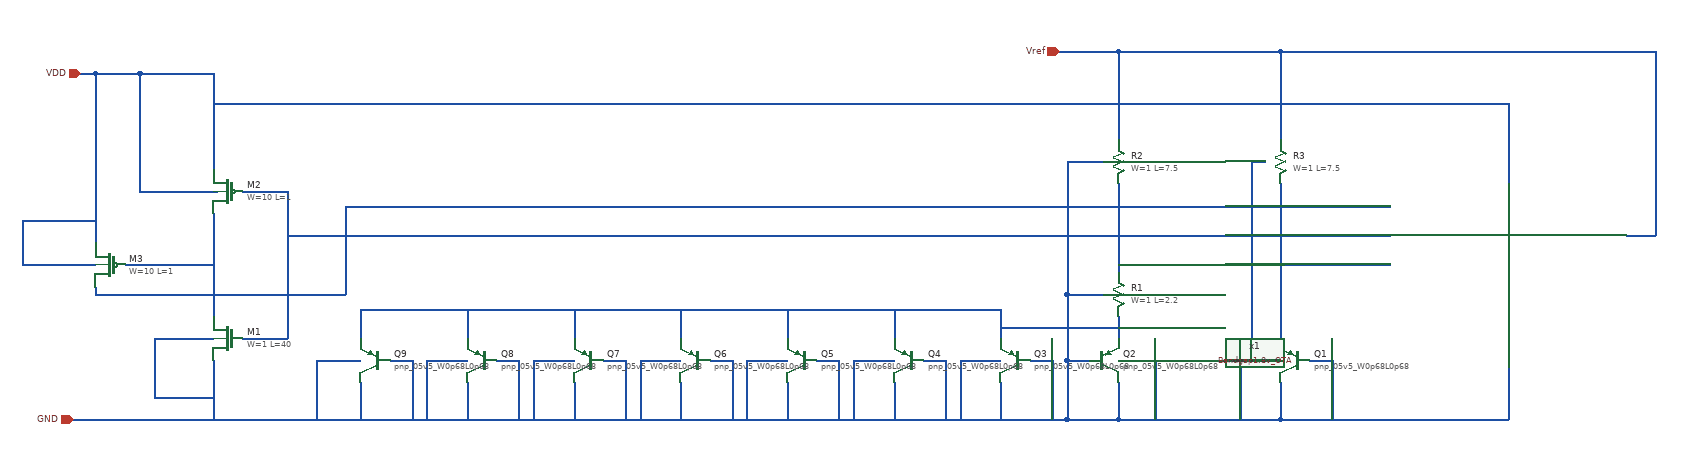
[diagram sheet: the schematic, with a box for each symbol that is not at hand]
v {xschem version=2.9.9 file_version=1.2 }
G {}
K {}
V {}
S {}
E {}
N -950 -260 -950 -210 { lab=GND}
N -1170 -260 -1170 -210 { lab=GND}
N -1170 -210 -950 -210 { lab=GND}
N -1170 -350 -1170 -320 { lab=#net1}
N -1170 -530 -1170 -410 { lab=#net2}
N -1170 -710 -950 -710 { lab=Vref}
N -1170 -710 -1170 -590 { lab=Vref}
N -950 -210 -660 -210 { lab=GND}
N -1250 -710 -1170 -710 { lab=Vref}
N -910 -290 -880 -290 { lab=GND}
N -880 -290 -880 -210 { lab=GND}
N -1005 -290 -950 -290 { lab=GND}
N -1005 -290 -1005 -210 { lab=GND}
N -1170 -290 -1120 -290 { lab=GND}
N -1120 -290 -1120 -210 { lab=GND}
N -1240 -290 -1210 -290 { lab=GND}
N -1240 -290 -1240 -210 { lab=GND}
N -1240 -210 -1170 -210 { lab=GND}
N -1330 -260 -1330 -210 { lab=GND}
N -1290 -290 -1260 -290 { lab=GND}
N -1260 -290 -1260 -210 { lab=GND}
N -1385 -290 -1330 -290 { lab=GND}
N -1385 -290 -1385 -210 { lab=GND}
N -1475 -260 -1475 -210 { lab=GND}
N -1435 -290 -1405 -290 { lab=GND}
N -1405 -290 -1405 -210 { lab=GND}
N -1530 -290 -1475 -290 { lab=GND}
N -1530 -290 -1530 -210 { lab=GND}
N -1620 -260 -1620 -210 { lab=GND}
N -1580 -290 -1550 -290 { lab=GND}
N -1550 -290 -1550 -210 { lab=GND}
N -1675 -290 -1620 -290 { lab=GND}
N -1675 -290 -1675 -210 { lab=GND}
N -1765 -260 -1765 -210 { lab=GND}
N -1725 -290 -1695 -290 { lab=GND}
N -1695 -290 -1695 -210 { lab=GND}
N -1820 -290 -1765 -290 { lab=GND}
N -1820 -290 -1820 -210 { lab=GND}
N -1910 -260 -1910 -210 { lab=GND}
N -1870 -290 -1840 -290 { lab=GND}
N -1840 -290 -1840 -210 { lab=GND}
N -1965 -290 -1910 -290 { lab=GND}
N -1965 -290 -1965 -210 { lab=GND}
N -2055 -260 -2055 -210 { lab=GND}
N -2015 -290 -1985 -290 { lab=GND}
N -1985 -290 -1985 -210 { lab=GND}
N -2110 -290 -2055 -290 { lab=GND}
N -2110 -290 -2110 -210 { lab=GND}
N -2200 -260 -2200 -210 { lab=GND}
N -2160 -290 -2130 -290 { lab=GND}
N -2130 -290 -2130 -210 { lab=GND}
N -2200 -360 -1330 -360 { lab=#net1}
N -1330 -360 -1330 -320 { lab=#net1}
N -1330 -335 -1170 -335 { lab=#net1}
N -1475 -360 -1475 -320 { lab=#net1}
N -1620 -360 -1620 -320 { lab=#net1}
N -1765 -360 -1765 -320 { lab=#net1}
N -1910 -360 -1910 -320 { lab=#net1}
N -2055 -360 -2055 -320 { lab=#net1}
N -2200 -360 -2200 -320 { lab=#net1}
N -950 -530 -950 -320 { lab=#net3}
N -950 -710 -950 -590 { lab=Vref}
N -1240 -380 -1190 -380 { lab=GND}
N -1240 -380 -1240 -290 { lab=GND}
N -1240 -560 -1190 -560 { lab=GND}
N -1240 -560 -1240 -380 { lab=GND}
N -990 -560 -990 -290 { lab=GND}
N -990 -560 -970 -560 { lab=GND}
N -660 -210 -650 -210 { lab=GND}
N -650 -210 -640 -210 { lab=GND}
N -2290 -210 -1240 -210 { lab=GND}
N -2260 -290 -2200 -290 { lab=GND}
N -2260 -290 -2260 -210 { lab=GND}
N -640 -640 -640 -530 { lab=VDD}
N -640 -390 -640 -210 { lab=GND}
N -480 -460 -440 -460 { lab=Vref}
N -440 -710 -440 -460 { lab=Vref}
N -950 -710 -440 -710 { lab=Vref}
N -950 -500 -800 -500 { lab=#net3}
N -1170 -420 -800 -420 { lab=#net2}
N -2400 -490 -2400 -350 { lab=#net4}
N -2360 -320 -2300 -320 { lab=#net5}
N -2300 -520 -2300 -320 { lab=#net5}
N -2360 -520 -2300 -520 { lab=#net5}
N -2520 -420 -2400 -420 { lab=#net4}
N -2400 -600 -2400 -550 { lab=VDD}
N -2400 -290 -2400 -210 { lab=GND}
N -2480 -320 -2400 -320 { lab=GND}
N -2480 -320 -2480 -240 { lab=GND}
N -2480 -240 -2400 -240 { lab=GND}
N -2500 -520 -2395 -520 { lab=VDD}
N -2660 -480 -2660 -420 { lab=VDD}
N -2660 -480 -2560 -480 { lab=VDD}
N -2560 -390 -2560 -380 { lab=#net3}
N -2400 -680 -2400 -600 { lab=VDD}
N -2500 -680 -2500 -520 { lab=VDD}
N -2500 -680 -2400 -680 { lab=VDD}
N -2560 -680 -2560 -450 { lab=VDD}
N -2560 -680 -2500 -680 { lab=VDD}
N -2580 -680 -2560 -680 { lab=VDD}
N -2590 -210 -2290 -210 { lab=GND}
N -2220 -500 -950 -500 { lab=#net3}
N -2220 -500 -2220 -380 { lab=#net3}
N -2560 -380 -2220 -380 { lab=#net3}
N -2660 -420 -2560 -420 { lab=VDD}
N -2300 -460 -800 -460 { lab=#net5}
N -2400 -640 -640 -640 { lab=VDD}
C {sky130_fd_pr/pnp_05v5.sym} -930 -290 0 1 {name=Q1
model=pnp_05v5_W0p68L0p68
spiceprefix=X
}
C {sky130_fd_pr/pnp_05v5.sym} -1190 -290 0 0 {name=Q2
model=pnp_05v5_W0p68L0p68
spiceprefix=X
}
C {sky130_fd_pr/pnp_05v5.sym} -1310 -290 0 1 {name=Q3
model=pnp_05v5_W0p68L0p68
spiceprefix=X
}
C {sky130_fd_pr/pnp_05v5.sym} -1455 -290 0 1 {name=Q4
model=pnp_05v5_W0p68L0p68
spiceprefix=X
}
C {sky130_fd_pr/pnp_05v5.sym} -1600 -290 0 1 {name=Q5
model=pnp_05v5_W0p68L0p68
spiceprefix=X
}
C {sky130_fd_pr/pnp_05v5.sym} -1745 -290 0 1 {name=Q6
model=pnp_05v5_W0p68L0p68
spiceprefix=X
}
C {sky130_fd_pr/pnp_05v5.sym} -1890 -290 0 1 {name=Q7
model=pnp_05v5_W0p68L0p68
spiceprefix=X
}
C {sky130_fd_pr/pnp_05v5.sym} -2035 -290 0 1 {name=Q8
model=pnp_05v5_W0p68L0p68
spiceprefix=X
}
C {sky130_fd_pr/pnp_05v5.sym} -2180 -290 0 1 {name=Q9
model=pnp_05v5_W0p68L0p68
spiceprefix=X
}
C {devices/opin.sym} -1250 -710 0 1 {name=p3 lab=Vref}
C {sky130_fd_pr/res_xhigh_po.sym} -1170 -380 0 0 {name=R1
W=1
L=2.2
model=res_xhigh_po
spiceprefix=X
mult=1}
C {sky130_fd_pr/res_xhigh_po.sym} -1170 -560 0 0 {name=R2
W=1
L=7.5
model=res_xhigh_po
spiceprefix=X
mult=1}
C {sky130_fd_pr/res_xhigh_po.sym} -950 -560 0 0 {name=R3
W=1
L=7.5
model=res_xhigh_po
spiceprefix=X
mult=1}
C {sky130_fd_pr/pfet_g5v0d10v5.sym} -2380 -520 0 1 {name=M2
L=1
W=10
nf=1
mult=1
ad="'int((nf+1)/2) * W/nf * 0.29'" 
pd="'2*int((nf+1)/2) * (W/nf + 0.29)'"
as="'int((nf+2)/2) * W/nf * 0.29'" 
ps="'2*int((nf+2)/2) * (W/nf + 0.29)'"
nrd="'0.29 / W'" nrs="'0.29 / W'"
sa=0 sb=0 sd=0
model=pfet_g5v0d10v5
spiceprefix=X
}
C {sky130_fd_pr/pfet_g5v0d10v5.sym} -2540 -420 0 1 {name=M3
L=1
W=10
nf=1
mult=1
ad="'int((nf+1)/2) * W/nf * 0.29'" 
pd="'2*int((nf+1)/2) * (W/nf + 0.29)'"
as="'int((nf+2)/2) * W/nf * 0.29'" 
ps="'2*int((nf+2)/2) * (W/nf + 0.29)'"
nrd="'0.29 / W'" nrs="'0.29 / W'"
sa=0 sb=0 sd=0
model=pfet_g5v0d10v5
spiceprefix=X
}
C {sky130_fd_pr/nfet_g5v0d10v5.sym} -2380 -320 0 1 {name=M1
L=40
W=1
nf=1
mult=1
ad="'int((nf+1)/2) * W/nf * 0.29'" 
pd="'2*int((nf+1)/2) * (W/nf + 0.29)'"
as="'int((nf+2)/2) * W/nf * 0.29'" 
ps="'2*int((nf+2)/2) * (W/nf + 0.29)'"
nrd="'0.29 / W'" nrs="'0.29 / W'"
sa=0 sb=0 sd=0
model=nfet_g5v0d10v5
spiceprefix=X
}
C {devices/ipin.sym} -2580 -680 0 0 {name=p4 lab=VDD}
C {devices/ipin.sym} -2590 -210 0 0 {name=p5 lab=GND}
C {/home/eslam/Analog_Design/Analog_Blocks/LDO/Schematic/LDO_Miller_1.8v/Bandgap1.8v_OTA.sym} -640 -460 0 0 {name=x1}
